One B-rep face of a CAD part: STEP entity #73314.
In plain terms, the planar face has unit normal (0, 0, 1).
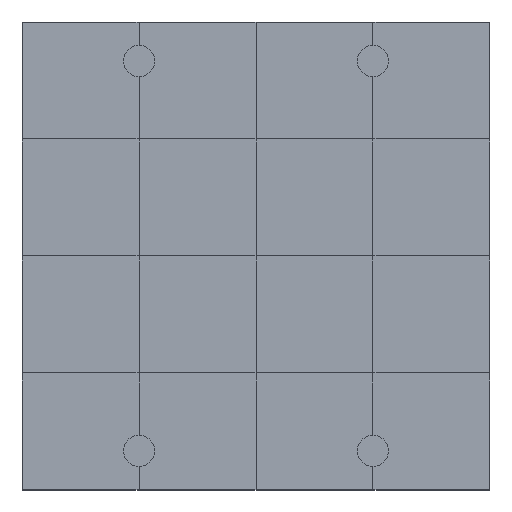
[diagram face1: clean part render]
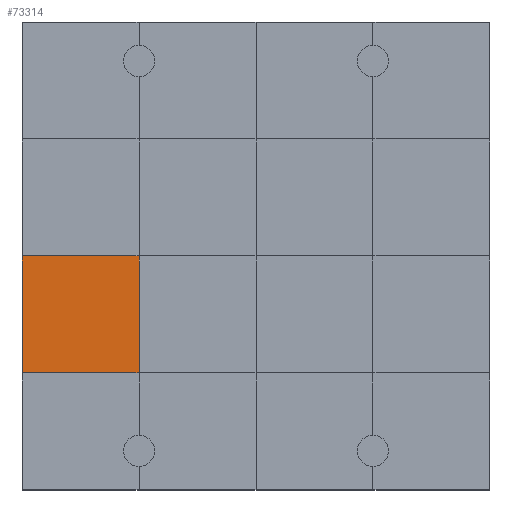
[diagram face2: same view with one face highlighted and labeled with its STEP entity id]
Its self-contained STEP definition (entity closure, numbers rounded to 3 decimals):
#72864 = VERTEX_POINT('',#72865);
#72865 = CARTESIAN_POINT('',(0.,3.,1.2));
#72879 = PLANE('',#72880);
#72880 = AXIS2_PLACEMENT_3D('',#72881,#72882,#72883);
#72881 = CARTESIAN_POINT('',(0.,3.,0.));
#72882 = DIRECTION('',(1.,0.,-0.));
#72883 = DIRECTION('',(0.,0.,1.));
#72905 = PLANE('',#72906);
#72906 = AXIS2_PLACEMENT_3D('',#72907,#72908,#72909);
#72907 = CARTESIAN_POINT('',(0.,0.,1.2));
#72908 = DIRECTION('',(0.,0.,1.));
#72909 = DIRECTION('',(1.,0.,-0.));
#73056 = VERTEX_POINT('',#73057);
#73057 = CARTESIAN_POINT('',(3.,3.,1.2));
#73078 = EDGE_CURVE('',#72864,#73056,#73079,.T.);
#73079 = SURFACE_CURVE('',#73080,(#73084,#73091),.PCURVE_S1.);
#73080 = LINE('',#73081,#73082);
#73081 = CARTESIAN_POINT('',(0.,3.,1.2));
#73082 = VECTOR('',#73083,1.);
#73083 = DIRECTION('',(1.,0.,-0.));
#73084 = PCURVE('',#72905,#73085);
#73085 = DEFINITIONAL_REPRESENTATION('',(#73086),#73090);
#73086 = LINE('',#73087,#73088);
#73087 = CARTESIAN_POINT('',(0.,3.));
#73088 = VECTOR('',#73089,1.);
#73089 = DIRECTION('',(1.,0.));
#73090 = ( GEOMETRIC_REPRESENTATION_CONTEXT(2) 
PARAMETRIC_REPRESENTATION_CONTEXT() REPRESENTATION_CONTEXT('2D SPACE',''
  ) );
#73091 = PCURVE('',#73092,#73097);
#73092 = PLANE('',#73093);
#73093 = AXIS2_PLACEMENT_3D('',#73094,#73095,#73096);
#73094 = CARTESIAN_POINT('',(0.,3.,1.2));
#73095 = DIRECTION('',(0.,0.,1.));
#73096 = DIRECTION('',(1.,0.,-0.));
#73097 = DEFINITIONAL_REPRESENTATION('',(#73098),#73102);
#73098 = LINE('',#73099,#73100);
#73099 = CARTESIAN_POINT('',(0.,0.));
#73100 = VECTOR('',#73101,1.);
#73101 = DIRECTION('',(1.,0.));
#73102 = ( GEOMETRIC_REPRESENTATION_CONTEXT(2) 
PARAMETRIC_REPRESENTATION_CONTEXT() REPRESENTATION_CONTEXT('2D SPACE',''
  ) );
#73137 = VERTEX_POINT('',#73138);
#73138 = CARTESIAN_POINT('',(0.,6.,1.2));
#73164 = EDGE_CURVE('',#72864,#73137,#73165,.T.);
#73165 = SURFACE_CURVE('',#73166,(#73170,#73177),.PCURVE_S1.);
#73166 = LINE('',#73167,#73168);
#73167 = CARTESIAN_POINT('',(0.,3.,1.2));
#73168 = VECTOR('',#73169,1.);
#73169 = DIRECTION('',(-0.,1.,0.));
#73170 = PCURVE('',#72879,#73171);
#73171 = DEFINITIONAL_REPRESENTATION('',(#73172),#73176);
#73172 = LINE('',#73173,#73174);
#73173 = CARTESIAN_POINT('',(1.2,0.));
#73174 = VECTOR('',#73175,1.);
#73175 = DIRECTION('',(0.,-1.));
#73176 = ( GEOMETRIC_REPRESENTATION_CONTEXT(2) 
PARAMETRIC_REPRESENTATION_CONTEXT() REPRESENTATION_CONTEXT('2D SPACE',''
  ) );
#73177 = PCURVE('',#73092,#73178);
#73178 = DEFINITIONAL_REPRESENTATION('',(#73179),#73183);
#73179 = LINE('',#73180,#73181);
#73180 = CARTESIAN_POINT('',(0.,0.));
#73181 = VECTOR('',#73182,1.);
#73182 = DIRECTION('',(0.,1.));
#73183 = ( GEOMETRIC_REPRESENTATION_CONTEXT(2) 
PARAMETRIC_REPRESENTATION_CONTEXT() REPRESENTATION_CONTEXT('2D SPACE',''
  ) );
#73314 = ADVANCED_FACE('',(#73315),#73092,.T.);
#73315 = FACE_BOUND('',#73316,.T.);
#73316 = EDGE_LOOP('',(#73317,#73318,#73319,#73347));
#73317 = ORIENTED_EDGE('',*,*,#73164,.F.);
#73318 = ORIENTED_EDGE('',*,*,#73078,.T.);
#73319 = ORIENTED_EDGE('',*,*,#73320,.T.);
#73320 = EDGE_CURVE('',#73056,#73321,#73323,.T.);
#73321 = VERTEX_POINT('',#73322);
#73322 = CARTESIAN_POINT('',(3.,6.,1.2));
#73323 = SURFACE_CURVE('',#73324,(#73328,#73335),.PCURVE_S1.);
#73324 = LINE('',#73325,#73326);
#73325 = CARTESIAN_POINT('',(3.,3.,1.2));
#73326 = VECTOR('',#73327,1.);
#73327 = DIRECTION('',(-0.,1.,0.));
#73328 = PCURVE('',#73092,#73329);
#73329 = DEFINITIONAL_REPRESENTATION('',(#73330),#73334);
#73330 = LINE('',#73331,#73332);
#73331 = CARTESIAN_POINT('',(3.,0.));
#73332 = VECTOR('',#73333,1.);
#73333 = DIRECTION('',(0.,1.));
#73334 = ( GEOMETRIC_REPRESENTATION_CONTEXT(2) 
PARAMETRIC_REPRESENTATION_CONTEXT() REPRESENTATION_CONTEXT('2D SPACE',''
  ) );
#73335 = PCURVE('',#73336,#73341);
#73336 = PLANE('',#73337);
#73337 = AXIS2_PLACEMENT_3D('',#73338,#73339,#73340);
#73338 = CARTESIAN_POINT('',(3.,3.,1.2));
#73339 = DIRECTION('',(0.,0.,1.));
#73340 = DIRECTION('',(1.,0.,-0.));
#73341 = DEFINITIONAL_REPRESENTATION('',(#73342),#73346);
#73342 = LINE('',#73343,#73344);
#73343 = CARTESIAN_POINT('',(0.,0.));
#73344 = VECTOR('',#73345,1.);
#73345 = DIRECTION('',(0.,1.));
#73346 = ( GEOMETRIC_REPRESENTATION_CONTEXT(2) 
PARAMETRIC_REPRESENTATION_CONTEXT() REPRESENTATION_CONTEXT('2D SPACE',''
  ) );
#73347 = ORIENTED_EDGE('',*,*,#73348,.F.);
#73348 = EDGE_CURVE('',#73137,#73321,#73349,.T.);
#73349 = SURFACE_CURVE('',#73350,(#73354,#73361),.PCURVE_S1.);
#73350 = LINE('',#73351,#73352);
#73351 = CARTESIAN_POINT('',(0.,6.,1.2));
#73352 = VECTOR('',#73353,1.);
#73353 = DIRECTION('',(1.,0.,-0.));
#73354 = PCURVE('',#73092,#73355);
#73355 = DEFINITIONAL_REPRESENTATION('',(#73356),#73360);
#73356 = LINE('',#73357,#73358);
#73357 = CARTESIAN_POINT('',(0.,3.));
#73358 = VECTOR('',#73359,1.);
#73359 = DIRECTION('',(1.,0.));
#73360 = ( GEOMETRIC_REPRESENTATION_CONTEXT(2) 
PARAMETRIC_REPRESENTATION_CONTEXT() REPRESENTATION_CONTEXT('2D SPACE',''
  ) );
#73361 = PCURVE('',#73362,#73367);
#73362 = PLANE('',#73363);
#73363 = AXIS2_PLACEMENT_3D('',#73364,#73365,#73366);
#73364 = CARTESIAN_POINT('',(0.,6.,1.2));
#73365 = DIRECTION('',(0.,0.,1.));
#73366 = DIRECTION('',(1.,0.,-0.));
#73367 = DEFINITIONAL_REPRESENTATION('',(#73368),#73372);
#73368 = LINE('',#73369,#73370);
#73369 = CARTESIAN_POINT('',(0.,0.));
#73370 = VECTOR('',#73371,1.);
#73371 = DIRECTION('',(1.,0.));
#73372 = ( GEOMETRIC_REPRESENTATION_CONTEXT(2) 
PARAMETRIC_REPRESENTATION_CONTEXT() REPRESENTATION_CONTEXT('2D SPACE',''
  ) );
